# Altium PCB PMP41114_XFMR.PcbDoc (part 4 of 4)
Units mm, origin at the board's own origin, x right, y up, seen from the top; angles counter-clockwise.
Board outline 70 x 173.04 mm, 10 copper layers (Top Layer, Layer 2, Layer 3, Layer 4, Layer 5, Layer 6, Layer 7, Layer 8, Layer 9, Bottom Layer 1), stack 2.98 mm thick; 144 components, 147 nets, 541 pads, 962 vias.
Unrouted connection lines stored in the file: 2.

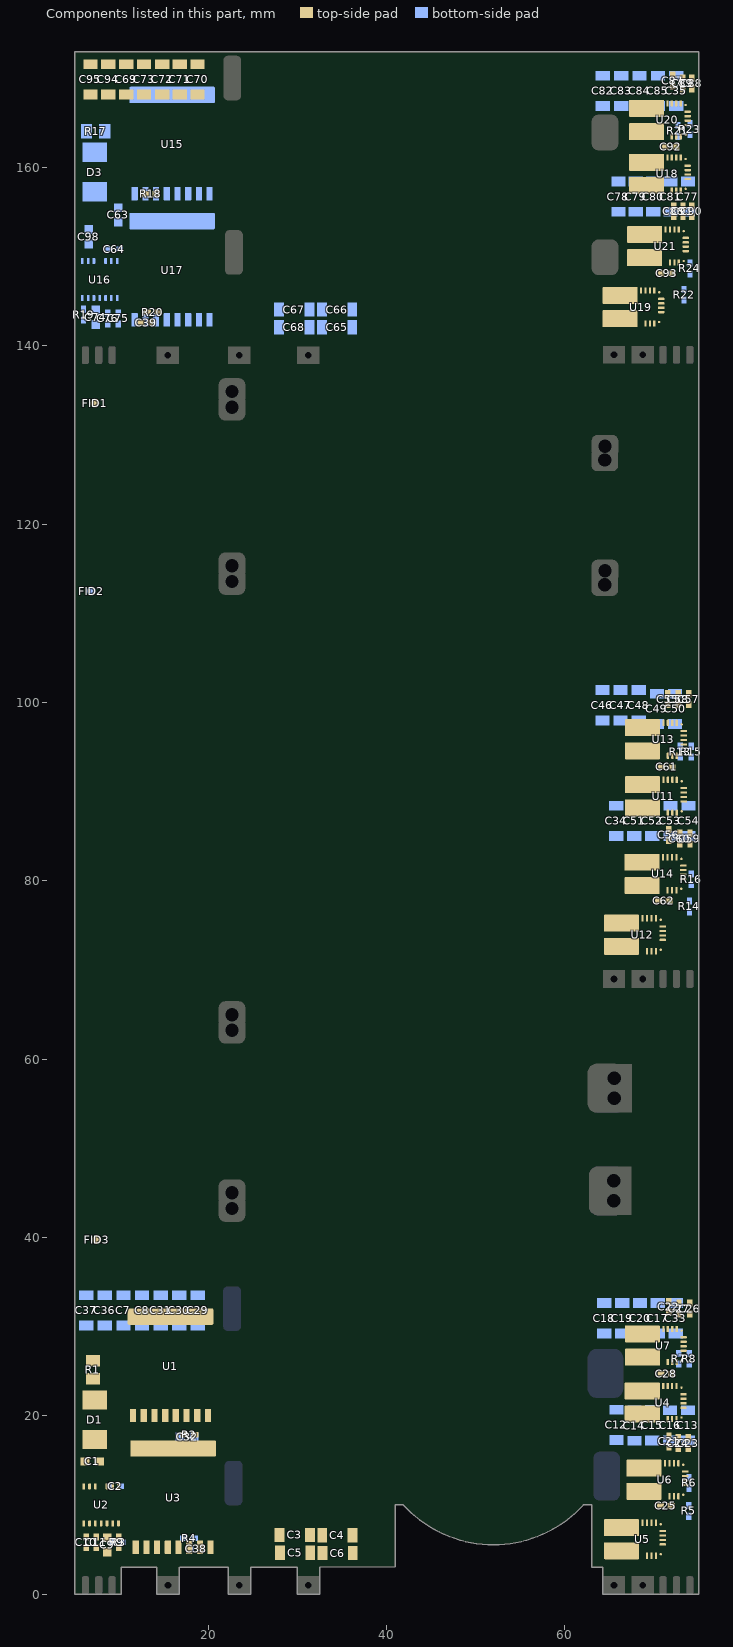
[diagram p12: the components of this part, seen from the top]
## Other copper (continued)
Layer 5:
  rectangle net B+_2: 5.479,29.71 21.197,31.729
  rectangle net Pri-SW_2: 21.821,29.443 24.74,34.307
  rectangle net Pri-Mid1_2: 35.515,3.537 37.264,7.513
  pour cut-out: 41.094,115.914 42.614,115.914 43.122,115.406 43.122,113.701 42.645,113.223 41.094,113.223
  pour cut-out: 10.564,154.799 11.055,155.291 20.429,155.291 20.914,154.805 20.914,153.478 20.404,152.967 11.056,152.967 10.564,153.46
  pour cut-out: 22.994,147.936 22.75,148.437 22.75,152.749 22.943,152.942 23.927,152.942 24.172,152.697 24.172,148.437 23.927,147.936
  pour cut-out: 15.119,157.57 cw(c15.119,158.29) 14.399,158.29 cw(c15.119,158.29) 15.119,159.01 cw(c15.119,158.29) 15.839,158.29 cw(c15.119,158.29)
  pour cut-out: 12.923,157.302 cw(c12.923,158.022) 12.203,158.022 cw(c12.923,158.022) 12.923,158.742 cw(c12.923,158.022) 13.643,158.022 cw(c12.923,158.022)
  pour cut-out: 11.02,156.256 cw(c11.02,156.976) 10.3,156.976 cw(c11.02,156.976) 11.02,157.696 cw(c11.02,156.976) 11.74,156.976 cw(c11.02,156.976)
  pour cut-out: 5.627,164.03 cw(c5.627,164.75) 4.907,164.75 cw(c5.627,164.75) 5.627,165.47 cw(c5.627,164.75) 6.347,164.75 cw(c5.627,164.75)
  pour cut-out: 5.768,153.639 cw(c5.768,154.359) 5.048,154.359 cw(c5.768,154.359) 5.768,155.079 cw(c5.768,154.359) 6.488,154.359 cw(c5.768,154.359)
  pour cut-out: 6.589,152.318 cw(c6.589,153.038) 5.869,153.038 cw(c6.589,153.038) 6.589,153.758 cw(c6.589,153.038) 7.309,153.038 cw(c6.589,153.038)
  pour cut-out: 6.589,150.718 cw(c6.589,151.438) 5.869,151.438 cw(c6.589,151.438) 6.589,152.158 cw(c6.589,151.438) 7.309,151.438 cw(c6.589,151.438)
  pour cut-out: 6.31,149.551 cw(c6.31,150.271) 5.59,150.271 cw(c6.31,150.271) 6.31,150.991 cw(c6.31,150.271) 7.03,150.271 cw(c6.31,150.271)
  pour cut-out: 52.038,79.072 cw(c52.038,87.072) 44.038,87.072 cw(c52.038,87.072) 52.038,95.072 cw(c52.038,87.072) 60.038,87.072 cw(c52.038,87.072)
  pour cut-out: 6.25,24.875 cw(c6.25,25.595) 5.53,25.595 cw(c6.25,25.595) 6.25,26.315 cw(c6.25,25.595) 6.97,25.595 cw(c6.25,25.595)
  pour cut-out: 63,130.25 63,126.056 63.785,125.271 64.5,125.271 64.5,130.25
  pour cut-out: 62.986,111.714 62.986,115.908 63.772,116.693 64.486,116.693 64.486,111.713
  pour cut-out: 10.559,164.447 11.021,164.91 20.843,164.91 21.243,164.509 21.243,158.706 20.857,158.319 10.903,158.319 10.559,158.663
  pour cut-out: 24.945,160.25 26.83,160.25 27.338,159.742 27.338,158.037 26.86,157.56 24.954,157.56 24.495,158.019 24.495,159.799
  pour cut-out: 63.251,19.14 64.592,19.14 64.753,18.979 64.753,16.437 64.501,16.185 63.275,16.185 63.04,16.419 63.04,18.929
  pour cut-out: 32.274,22.438 52.276,19.373 52.276,18.693 32.139,21.889
  text ".Layer_Name" at 15.418,-21.806 h1.52
Layer 6:
  rectangle net B+_2: 5.479,29.71 21.197,31.729
  rectangle net Pri-SW_5: 22.075,168.063 24.567,172.449
  rectangle net Pri-SW_2: 11.005,21.919 20.37,27.371
  rectangle net Pri-SW_2: 22.851,29.934 23.588,34.329
  rectangle net Pri-Mid1_2: 35.515,3.537 37.264,7.513
  rectangle net Pri-Mid1_2: 27.275,3.61 29.023,7.586
  pour cut-out: 52.038,79.072 cw(c52.038,87.072) 44.038,87.072 cw(c52.038,87.072) 52.038,95.072 cw(c52.038,87.072) 60.038,87.072 cw(c52.038,87.072)
  pour cut-out: 63,130.25 63,126.056 63.785,125.271 64.5,125.271 64.5,130.25
  pour cut-out: 62.986,111.714 62.986,115.908 63.772,116.693 64.486,116.693 64.486,111.713
  pour cut-out: 37.75,54 38.011,53.739 40.486,53.739 41,54.253 41,55.46 40.43,56.03 38.169,56.03 37.75,55.612
  pour cut-out: 63.23,157.156 64.571,157.156 64.732,156.995 64.732,154.453 64.48,154.201 63.254,154.201 63.019,154.436 63.019,156.946
  pour cut-out: 21.125,167.563 21.125,141.449 21.491,141.449 21.491,167.614
  pour cut-out: 42.449,121.29 42.449,123.151 42.753,123.455 45.474,123.455 45.636,123.293 45.636,121.286 45.355,121.006 42.733,121.006
  pour cut-out: 32.274,22.438 52.276,19.373 52.276,18.693 32.139,21.889
  pour cut-out: 63.23,19.156 64.571,19.156 64.732,18.995 64.732,16.453 64.48,16.201 63.254,16.201 63.019,16.436 63.019,18.946
  text ".Layer_Name" at 16.489,-21.556 h1.52
Layer 7:
  rectangle net Pri-SW_5: 22.854,168.114 25.048,172.5
  rectangle net Pri-Mid1_2: 35.515,3.537 37.264,7.513
  rectangle net Pri-Mid1_2: 27.275,3.61 29.023,7.586
  rectangle net Pri-SW_2: 11.005,21.919 20.37,27.371
  pour cut-out: 37.639,114.437 38.775,114.437 41,112.212 41,111.936 37.672,111.936 37.639,111.969
  pour cut-out: 23.491,8.148 22.8,8.169 22.43,8.453 22.43,14.592 22.622,14.784 23.607,14.784 23.851,14.54 23.851,8.428
  pour cut-out: 17.865,18.271 cw(c17.865,18.991) 17.145,18.991 cw(c17.865,18.991) 17.865,19.711 cw(c17.865,18.991) 18.585,18.991 cw(c17.865,18.991)
  pour cut-out: 18.654,17.982 cw(c18.654,18.702) 17.934,18.702 cw(c18.654,18.702) 18.654,19.422 cw(c18.654,18.702) 19.374,18.702 cw(c18.654,18.702)
  pour cut-out: 19.486,17.926 cw(c19.486,18.646) 18.766,18.646 cw(c19.486,18.646) 19.486,19.366 cw(c19.486,18.646) 20.206,18.646 cw(c19.486,18.646)
  pour cut-out: 5.627,164.03 cw(c5.627,164.75) 4.907,164.75 cw(c5.627,164.75) 5.627,165.47 cw(c5.627,164.75) 6.347,164.75 cw(c5.627,164.75)
  pour cut-out: 52.038,79.072 cw(c52.038,87.072) 44.038,87.072 cw(c52.038,87.072) 52.038,95.072 cw(c52.038,87.072) 60.038,87.072 cw(c52.038,87.072)
  pour cut-out: 6.25,24.875 cw(c6.25,25.595) 5.53,25.595 cw(c6.25,25.595) 6.25,26.315 cw(c6.25,25.595) 6.97,25.595 cw(c6.25,25.595)
  pour cut-out: 63,130.25 63,126.056 63.785,125.271 64.5,125.271 64.5,130.25
  pour cut-out: 62.986,111.714 62.986,115.908 63.772,116.693 64.486,116.693 64.486,111.713
  pour cut-out: 36.508,51.807 36.508,53.148 36.757,53.397 38.88,53.397 39.275,53.002 39.275,51.904 38.898,51.526 36.789,51.526
  pour cut-out: 63.203,157.25 64.518,157.25 64.794,156.973 64.794,154.223 64.5,153.929 63.21,153.929 62.864,154.275 62.864,156.911
  pour cut-out: 24.534,161.537 25.088,162.09 26.904,162.09 27.42,161.574 27.42,160.456 27.043,160.078 24.977,160.078 24.534,160.521
  pour cut-out: 10.372,27.538 10.834,28 20.656,28 21.057,27.599 21.057,21.796 20.67,21.409 10.716,21.409 10.372,21.754
  pour cut-out: 32.274,22.438 52.276,19.373 52.276,18.693 32.139,21.889
  pour cut-out: 63.298,19.187 64.544,19.187 64.753,18.979 64.753,16.437 64.41,16.094 63.366,16.094 63.04,16.419 63.04,18.929
  text ".Layer_Name" at 17.518,-21.806 h1.52
Layer 8:
  rectangle net Pri-SW_2: 11.005,21.919 20.37,27.371
  rectangle net Pri-SW_5: 24.88,160.462 26.992,161.755
  rectangle net Pri-SW_5: 22.854,168.114 25.347,172.5
  rectangle net Pri-Mid1_2: 35.515,3.537 37.264,7.513
  pour cut-out: 37.639,114.437 38.775,114.437 41,112.212 41,111.936 37.672,111.936 37.639,111.969
  pour cut-out: 22.487,34.513 23.908,34.469 23.908,29.862 23.716,29.669 22.731,29.669 22.487,29.914
  pour cut-out: 28.524,22.623 28.524,24.815 25.326,24.815 24.804,24.294 24.804,23.109 25.29,22.623
  pour cut-out: 6.701,12.261 cw(c6.701,12.981) 5.981,12.981 cw(c6.701,12.981) 6.701,13.701 cw(c6.701,12.981) 7.421,12.981 cw(c6.701,12.981)
  pour cut-out: 5.808,12.572 cw(c5.808,13.292) 5.088,13.292 cw(c5.808,13.292) 5.808,14.012 cw(c5.808,13.292) 6.528,13.292 cw(c5.808,13.292)
  pour cut-out: 6.678,13.09 cw(c6.678,13.81) 5.958,13.81 cw(c6.678,13.81) 6.678,14.53 cw(c6.678,13.81) 7.398,13.81 cw(c6.678,13.81)
  pour cut-out: 6.25,24.875 cw(c6.25,25.595) 5.53,25.595 cw(c6.25,25.595) 6.25,26.315 cw(c6.25,25.595) 6.97,25.595 cw(c6.25,25.595)
  pour cut-out: 10.372,27.538 10.834,28 20.656,28 21.057,27.599 21.057,21.796 20.67,21.409 10.716,21.409 10.372,21.754
  pour cut-out: 18.654,17.982 cw(c18.654,18.702) 17.934,18.702 cw(c18.654,18.702) 18.654,19.422 cw(c18.654,18.702) 19.374,18.702 cw(c18.654,18.702)
  pour cut-out: 17.865,18.271 cw(c17.865,18.991) 17.145,18.991 cw(c17.865,18.991) 17.865,19.711 cw(c17.865,18.991) 18.585,18.991 cw(c17.865,18.991)
  pour cut-out: 19.486,17.926 cw(c19.486,18.646) 18.766,18.646 cw(c19.486,18.646) 19.486,19.366 cw(c19.486,18.646) 20.206,18.646 cw(c19.486,18.646)
  pour cut-out: 23.491,8.148 22.8,8.169 22.43,8.453 22.43,14.592 22.622,14.784 23.607,14.784 23.851,14.54 23.851,8.428
  pour cut-out: 10.564,154.799 11.055,155.291 20.429,155.291 20.914,154.805 20.914,153.478 20.404,152.967 11.056,152.967 10.564,153.46
  pour cut-out: 22.994,147.936 22.75,148.437 22.75,152.749 22.943,152.942 23.927,152.942 24.172,152.697 24.172,148.437 23.927,147.936
  pour cut-out: 23.238,167.686 cw(c23.238,168.406) 22.518,168.406 cw(c23.238,168.406) 23.238,169.126 cw(c23.238,168.406) 23.958,168.406 cw(c23.238,168.406)
  pour cut-out: 23.235,169.117 cw(c23.235,169.837) 22.515,169.837 cw(c23.235,169.837) 23.235,170.557 cw(c23.235,169.837) 23.955,169.837 cw(c23.235,169.837)
  pour cut-out: 23.238,168.406 cw(c23.238,169.126) 22.518,169.126 cw(c23.238,169.126) 23.238,169.846 cw(c23.238,169.126) 23.958,169.126 cw(c23.238,169.126)
  pour cut-out: 6.31,149.551 cw(c6.31,150.271) 5.59,150.271 cw(c6.31,150.271) 6.31,150.991 cw(c6.31,150.271) 7.03,150.271 cw(c6.31,150.271)
  pour cut-out: 6.589,150.718 cw(c6.589,151.438) 5.869,151.438 cw(c6.589,151.438) 6.589,152.158 cw(c6.589,151.438) 7.309,151.438 cw(c6.589,151.438)
  pour cut-out: 6.589,152.318 cw(c6.589,153.038) 5.869,153.038 cw(c6.589,153.038) 6.589,153.758 cw(c6.589,153.038) 7.309,153.038 cw(c6.589,153.038)
  pour cut-out: 5.768,153.639 cw(c5.768,154.359) 5.048,154.359 cw(c5.768,154.359) 5.768,155.079 cw(c5.768,154.359) 6.488,154.359 cw(c5.768,154.359)
  pour cut-out: 5.627,164.03 cw(c5.627,164.75) 4.907,164.75 cw(c5.627,164.75) 5.627,165.47 cw(c5.627,164.75) 6.347,164.75 cw(c5.627,164.75)
  pour cut-out: 11.02,156.256 cw(c11.02,156.976) 10.3,156.976 cw(c11.02,156.976) 11.02,157.696 cw(c11.02,156.976) 11.74,156.976 cw(c11.02,156.976)
  pour cut-out: 12.923,157.302 cw(c12.923,158.022) 12.203,158.022 cw(c12.923,158.022) 12.923,158.742 cw(c12.923,158.022) 13.643,158.022 cw(c12.923,158.022)
  pour cut-out: 15.119,157.57 cw(c15.119,158.29) 14.399,158.29 cw(c15.119,158.29) 15.119,159.01 cw(c15.119,158.29) 15.839,158.29 cw(c15.119,158.29)
  pour cut-out: 52.038,79.072 cw(c52.038,87.072) 44.038,87.072 cw(c52.038,87.072) 52.038,95.072 cw(c52.038,87.072) 60.038,87.072 cw(c52.038,87.072)
  pour cut-out: 6.25,24.875 cw(c6.25,25.595) 5.53,25.595 cw(c6.25,25.595) 6.25,26.315 cw(c6.25,25.595) 6.97,25.595 cw(c6.25,25.595)
  pour cut-out: 63,130.25 63,126.056 63.785,125.271 64.5,125.271 64.5,130.25
  pour cut-out: 62.986,111.714 62.986,115.908 63.772,116.693 64.486,116.693 64.486,111.713
  pour cut-out: 10.559,164.447 11.021,164.91 20.843,164.91 21.243,164.509 21.243,158.706 20.857,158.319 10.903,158.319 10.559,158.663
  pour cut-out: 63.298,87.187 64.544,87.187 64.753,86.979 64.753,84.437 64.41,84.094 63.366,84.094 63.04,84.419 63.04,86.929
  pour cut-out: 63.298,19.187 64.544,19.187 64.753,18.979 64.753,16.437 64.41,16.094 63.366,16.094 63.04,16.419 63.04,18.929
  pour cut-out: 36.527,52.047 36.527,52.953 37.042,53.469 38.982,53.469 39.276,53.175 39.276,51.519 37.055,51.519
  text ".Layer_Name" at 18.685,-21.556 h1.52
Layer 2:
  rectangle net 54Vout_5: 64.25,138.321 66.756,140.899
  rectangle net 54Vout_4: 64.25,68.321 66.756,70.899
  rectangle net 54Vout_2: 64.25,0.321 66.756,2.899
  rectangle net Pri-SW_2: 22.851,29.523 26.129,34.409
  rectangle net Pri-SW_2: 22.851,29.545 23.588,34.409
  rectangle net Pri-Mid1_2: 27.053,3.657 28.725,7.513
  rectangle net Pri-Mid1_2: 35.515,3.537 37.264,7.513
  rectangle net Pri-SW_2: 11.231,21.858 20.482,27.384
  pour cut-out: 24.692,161.794 24.989,162.09 27.324,162.09 27.42,161.994 27.42,160.456 27.043,160.078 24.977,160.078 24.692,160.363
  pour cut-out: 41.043,115.853 42.594,115.853 43.038,115.408 43.038,113.351 41.076,113.351 41.043,113.384
  pour cut-out: 37.639,114.437 38.775,114.437 41,112.212 41,111.936 37.672,111.936 37.639,111.969
  pour cut-out: 31.957,117.944 cw(c31.957,124.462) 25.439,124.462 cw(c31.957,124.462) 31.957,130.979 cw(c31.957,124.462) 38.474,124.462 cw(c31.957,124.462)
  pour cut-out: 52.038,79.072 cw(c52.038,87.072) 44.038,87.072 cw(c52.038,87.072) 52.038,95.072 cw(c52.038,87.072) 60.038,87.072 cw(c52.038,87.072)
  pour cut-out: 19.264,30.282 cw(c19.264,31.002) 18.544,31.002 cw(c19.264,31.002) 19.264,31.722 cw(c19.264,31.002) 19.984,31.002 cw(c19.264,31.002)
  pour cut-out: 19.264,29.562 cw(c19.264,30.282) 18.544,30.282 cw(c19.264,30.282) 19.264,31.002 cw(c19.264,30.282) 19.984,30.282 cw(c19.264,30.282)
  pour cut-out: 16.858,30.275 cw(c16.858,30.995) 16.138,30.995 cw(c16.858,30.995) 16.858,31.715 cw(c16.858,30.995) 17.578,30.995 cw(c16.858,30.995)
  pour cut-out: 16.858,29.555 cw(c16.858,30.275) 16.138,30.275 cw(c16.858,30.275) 16.858,30.995 cw(c16.858,30.275) 17.578,30.275 cw(c16.858,30.275)
  pour cut-out: 14.453,30.269 cw(c14.453,30.989) 13.733,30.989 cw(c14.453,30.989) 14.453,31.709 cw(c14.453,30.989) 15.173,30.989 cw(c14.453,30.989)
  pour cut-out: 14.453,29.549 cw(c14.453,30.269) 13.733,30.269 cw(c14.453,30.269) 14.453,30.989 cw(c14.453,30.269) 15.173,30.269 cw(c14.453,30.269)
  pour cut-out: 12.048,29.542 cw(c12.048,30.262) 11.328,30.262 cw(c12.048,30.262) 12.048,30.982 cw(c12.048,30.262) 12.767,30.262 cw(c12.048,30.262)
  pour cut-out: 12.048,30.262 cw(c12.048,30.982) 11.328,30.982 cw(c12.048,30.982) 12.048,31.702 cw(c12.048,30.982) 12.767,30.982 cw(c12.048,30.982)
  pour cut-out: 9.642,29.536 cw(c9.642,30.256) 8.922,30.256 cw(c9.642,30.256) 9.642,30.976 cw(c9.642,30.256) 10.362,30.256 cw(c9.642,30.256)
  pour cut-out: 9.642,30.256 cw(c9.642,30.976) 8.922,30.976 cw(c9.642,30.976) 9.642,31.696 cw(c9.642,30.976) 10.362,30.976 cw(c9.642,30.976)
  pour cut-out: 7.237,29.526 cw(c7.237,30.246) 6.517,30.246 cw(c7.237,30.246) 7.237,30.966 cw(c7.237,30.246) 7.957,30.246 cw(c7.237,30.246)
  pour cut-out: 7.237,30.249 cw(c7.237,30.969) 6.517,30.969 cw(c7.237,30.969) 7.237,31.689 cw(c7.237,30.969) 7.957,30.969 cw(c7.237,30.969)
  pour cut-out: 63,130.25 63,126.056 63.785,125.271 64.5,125.271 64.5,130.25
  pour cut-out: 62.986,111.714 62.986,115.908 63.772,116.693 64.486,116.693 64.486,111.713
  pour cut-out: 32.311,55.872 52.003,52.856 51.561,49.158 31.442,52.331
  pour cut-out: 10.588,27.528 10.931,27.871 20.584,27.871 20.938,27.517 20.938,21.791 20.441,21.294 10.95,21.294 10.588,21.655
  pour cut-out: 32.038,124.719 51.867,121.681 51.691,120.205 31.703,123.358
  text ".Layer_Name" at 15.454,-21.556 h1.52
Layer 9:
  rectangle net Pri-SW_5: 24.88,160.462 26.992,161.755
  rectangle net Pri-SW_5: 22.776,167.712 24.809,172.5
  rectangle net Pri-SW_2: 22.243,29.581 24.172,34.409
  rectangle net Pri-Mid1_2: 35.515,3.537 37.264,7.513
  pour cut-out: 37.857,54.232 37.857,55.573 38.106,55.822 40.229,55.822 40.624,55.427 40.624,54.329 40.247,53.951 38.138,53.951
  pour cut-out: 10.564,154.799 11.055,155.291 20.429,155.291 20.914,154.805 20.914,153.478 20.404,152.967 11.056,152.967 10.564,153.46
  pour cut-out: 11.02,156.256 cw(c11.02,156.976) 10.3,156.976 cw(c11.02,156.976) 11.02,157.696 cw(c11.02,156.976) 11.74,156.976 cw(c11.02,156.976)
  pour cut-out: 12.923,157.302 cw(c12.923,158.022) 12.203,158.022 cw(c12.923,158.022) 12.923,158.742 cw(c12.923,158.022) 13.643,158.022 cw(c12.923,158.022)
  pour cut-out: 15.119,157.57 cw(c15.119,158.29) 14.399,158.29 cw(c15.119,158.29) 15.119,159.01 cw(c15.119,158.29) 15.839,158.29 cw(c15.119,158.29)
  pour cut-out: 18.943,168.023 cw(c18.943,168.743) 18.223,168.743 cw(c18.943,168.743) 18.943,169.463 cw(c18.943,168.743) 19.663,168.743 cw(c18.943,168.743)
  pour cut-out: 18.943,167.303 cw(c18.943,168.023) 18.223,168.023 cw(c18.943,168.023) 18.943,168.743 cw(c18.943,168.023) 19.663,168.023 cw(c18.943,168.023)
  pour cut-out: 16.537,168.017 cw(c16.537,168.737) 15.817,168.737 cw(c16.537,168.737) 16.537,169.457 cw(c16.537,168.737) 17.257,168.737 cw(c16.537,168.737)
  pour cut-out: 16.537,167.297 cw(c16.537,168.017) 15.817,168.017 cw(c16.537,168.017) 16.537,168.737 cw(c16.537,168.017) 17.257,168.017 cw(c16.537,168.017)
  pour cut-out: 14.132,168.01 cw(c14.132,168.73) 13.412,168.73 cw(c14.132,168.73) 14.132,169.45 cw(c14.132,168.73) 14.852,168.73 cw(c14.132,168.73)
  pour cut-out: 14.132,167.29 cw(c14.132,168.01) 13.412,168.01 cw(c14.132,168.01) 14.132,168.73 cw(c14.132,168.01) 14.852,168.01 cw(c14.132,168.01)
  pour cut-out: 11.726,167.284 cw(c11.726,168.004) 11.006,168.004 cw(c11.726,168.004) 11.726,168.724 cw(c11.726,168.004) 12.446,168.004 cw(c11.726,168.004)
  pour cut-out: 11.726,168.004 cw(c11.726,168.724) 11.006,168.724 cw(c11.726,168.724) 11.726,169.444 cw(c11.726,168.724) 12.446,168.724 cw(c11.726,168.724)
  pour cut-out: 9.321,167.277 cw(c9.321,167.997) 8.601,167.997 cw(c9.321,167.997) 9.321,168.717 cw(c9.321,167.997) 10.041,167.997 cw(c9.321,167.997)
  pour cut-out: 9.321,167.997 cw(c9.321,168.717) 8.601,168.717 cw(c9.321,168.717) 9.321,169.437 cw(c9.321,168.717) 10.041,168.717 cw(c9.321,168.717)
  pour cut-out: 6.915,167.268 cw(c6.915,167.987) 6.196,167.987 cw(c6.915,167.987) 6.915,168.707 cw(c6.915,167.987) 7.635,167.987 cw(c6.915,167.987)
  pour cut-out: 6.915,167.991 cw(c6.915,168.711) 6.196,168.711 cw(c6.915,168.711) 6.915,169.431 cw(c6.915,168.711) 7.635,168.711 cw(c6.915,168.711)
  pour cut-out: 52.038,79.072 cw(c52.038,87.072) 44.038,87.072 cw(c52.038,87.072) 52.038,95.072 cw(c52.038,87.072) 60.038,87.072 cw(c52.038,87.072)
  pour cut-out: 6.25,24.875 cw(c6.25,25.595) 5.53,25.595 cw(c6.25,25.595) 6.25,26.315 cw(c6.25,25.595) 6.97,25.595 cw(c6.25,25.595)
  pour cut-out: 62.986,111.714 62.986,115.908 63.772,116.693 64.486,116.693 64.486,111.713
  pour cut-out: 63,130.25 63,126.056 63.785,125.271 64.5,125.271 64.5,130.25
  pour cut-out: 10.559,164.447 11.021,164.91 20.843,164.91 21.243,164.509 21.243,158.706 20.857,158.319 10.903,158.319 10.559,158.663
  pour cut-out: 42.449,121.29 42.449,123.151 42.753,123.455 44.9,123.455 45.216,123.14 45.216,121.299 44.923,121.006 42.733,121.006
  pour cut-out: 36.508,51.807 36.508,53.148 36.757,53.397 38.88,53.397 39.275,53.002 39.275,51.904 38.898,51.526 36.789,51.526
  text ".Layer_Name" at 17.518,-21.556 h1.52
Bottom Layer 1:
  rectangle net Pri-Mid1_5: 22.802,148.1 23.993,152.348
  rectangle net Pri-Mid1_5: 35.367,141.21 37.473,145.589
  rectangle net Pri-Mid1_5: 26.868,141.194 28.534,145.382
  rectangle net Pri-SW_5: 22.559,167.211 23.749,172.5
  rectangle net Pri-Mid1_2: 27.053,3.657 28.725,7.513
  rectangle net Pri-Mid1_2: 35.515,3.537 37.264,7.513
  pour cut-out: 6.25,24.677 cw(c6.25,25.664) 5.263,25.664 cw(c6.217,25.631) 6.25,26.584 cw(c6.25,25.595) 7.239,25.595 cw(c6.286,25.631)
  text ".Layer_Name" at 14.656,-21.806 h1.52
Multi-Layer:
  rectangle net 54Vout_5: 64.25,138.321 66.756,140.899
  rectangle net 54Vout_4: 64.25,68.321 66.756,70.899
  rectangle net 54Vout_2: 64.25,0.321 66.756,2.899
  rectangle net B-_5: 11.192,144.862 20.557,150.254
  rectangle net Pri-SW_5: 11.192,159.01 20.557,164.403

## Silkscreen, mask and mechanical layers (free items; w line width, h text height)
Top Overlay:
  lines w0.254: 41,27.919 45.469,20.555 ; 41.096,9.603 45.565,16.967 ; 58.435,16.967 62.904,9.603 ; 58.531,20.555 63,27.919
  text "'.PRJ_Number'" at 44.528,9.333 h2
  text "H" at 5.958,2.966 h0.5
  text "G" at 7.578,2.966 h0.5
  text "L" at 9.127,2.966 h0.5
  text ".Layer_Name" at 14.656,-21.806 h1.52
Bottom Overlay:
  text "Z" at 9.407,3.226 h0.5
  text "V" at 6.461,3.207 h0.5
  text "G" at 7.81,3.207 h0.5
  text "54V" at 66.286,3.117 h0.5
  text "0V" at 69.044,3.117 h0.5
  text "PGND" at 16.52,3.039 h0.5
  text "HV" at 23.802,3.039 h0.5
  text "Mid" at 31.988,3.051 h0.5
  text "BH" at 72.739,2.557 h0.5
  text "AH" at 74.335,2.576 h0.5
  text "G" at 71.069,2.528 h0.5
  text ".Layer_Name" at 14.656,-21.806 h1.52
Top Paste:
  text ".Layer_Name" at 14.656,-21.806 h1.52
Bottom Paste:
  text ".Layer_Name" at 14.656,-21.806 h1.52
Top Solder:
  region: 20.63,144.688 20.63,151.273 10.95,151.273 10.95,144.688
  text ".Layer_Name" at 14.656,-21.806 h1.52
  text ".Layer_Name" at 14.656,-21.806 h1.52
Bottom Solder:
  region: 11.157,14.686 11.157,7.094 20.565,7.094 20.565,14.686
  region: 21.197,20.096 21.197,27.697 10.197,27.697 10.197,20.096
  text ".Layer_Name" at 14.656,-21.806 h1.52
Drill Guide:
  text ".Layer_Name" at 14.656,-21.806 h1.52
M1 Board Outline:
  drawing of 197 lines, arcs and shapes, not listed
  text "Bottom Layer" at 9.473,194.817 h0.76
  text "Bottom Layer" at 71.646,194.75 h0.76
  text "3+3 sec" at 59.652,192.6 h0.76
  text "3mm" at 72.055,192.6 h0.76
  text "4T pri" at 40.652,192.559 h0.76
  text "3mm" at 6.055,192.51 h0.76
  text "4T Lr" at 29.829,192.51 h0.76
  text "TopLayer" at 9.374,190.21 h0.76
  text "TopLayer" at 71.547,190.144 h0.76
  text "3mm" at 62.845,189.578 h0.76
  text "2T Lr" at 29.738,189.573 h0.76
  text "3mm" at 23.183,189.425 h0.76
  text "7T pri" at 40.652,189.425 h0.76
  text "3mm" at 71.902,186.614 h0.76
  text "0T pri" at 40.652,186.582 h0.76
  text "3+3+3 sec" at 59.652,186.461 h0.76
  text "7T pri" at 40.652,183.656 h0.76
  text "3mm" at 23.238,183.402 h0.76
  text "2T Lr" at 29.646,183.402 h0.76
  text "3mm" at 62.865,183.402 h0.76
  text "Bottom Layer" at 71.727,183.156 h0.76
  text "Bottom Layer" at 9.671,182.86 h0.76
  text "3+3 sec" at 59.902,180.705 h0.76
  text "3mm" at 5.903,180.659 h0.76
  text "4T pri" at 40.652,180.478 h0.76
  text "3mm" at 72.055,180.402 h0.76
  text "4T Lr" at 29.562,180.37 h0.76
  text "TopLayer" at 9.572,178.254 h0.76
  text "TopLayer" at 71.745,178.187 h0.76
  text ".Layer_Name" at 14.656,-21.806 h1.52
M2 Board Dimensions:
  rectangle: 0,-6.985 3.175,-3.81
  rectangle: 3.175,-10.16 12.7,-6.985
  lines w0.178: 0,-6.985 25.4,-6.985 ; 3.175,-10.16 3.175,-3.81 ; 6.35,-10.16 6.35,-3.81 ; 12.7,-10.16 12.7,-3.81 ; 19.05,-10.16 19.05,-3.81 ; 0,-10.16 25.4,-10.16 25.4,-3.81 0,-3.81 0,-10.16
  text ".Layer_Name" at 14.656,-21.806 h1.52
M3 3D STEP Top:
  text ".Layer_Name" at 14.656,-21.806 h1.52
M4 3D STEP Bottom:
  text ".Layer_Name" at 14.656,-21.806 h1.52
M5 Assembly Top:
  lines w0.254: -7.417,-23.626 160.223,-23.626 ; -7.417,-18.462 160.274,-18.462 ; -7.417,-13.297 -7.417,-28.791 94.31,-28.791 160.274,-28.791 160.274,-13.297 -7.404,-13.297 -7.404,-28.791 32.614,-28.791 ; 55.194,-28.791 55.194,-13.297 ; 87.376,-18.462 87.376,-13.297 ; 108.712,-18.462 108.712,-13.297 ; 124.511,-28.956 124.511,-23.804
  text "COMPONENTS MARKED 'DNP' SHOULD NOT BE POPULATED." at 29.299,-8.09 h1.52
  text "ASSEMBLY VARIANT:" at 29.286,-11.024 h1.52
  text ".VariantName" at 55.601,-11.024 h1.52
  text "PCB VIEWED FROM TOP SIDE" at -5.804,-16.654 h1.52
  text "BOARD #:" at 57.099,-16.654 h1.52
  text ".PRJ_Number" at 70.955,-16.654 h1.52
  text "REV:" at 92.405,-16.654 h1.52
  text ".PCB_Rev" at 99.809,-16.654 h1.52
  text "SVN REV:" at 113.69,-16.654 h1.52
  text ".VersionControl_RevNumber" at 126.543,-16.654 h1.52
  text "TID #:" at 57.099,-21.819 h1.52
  text ".TID" at 70.955,-21.819 h1.52
  text "PLOT NAME =" at -5.804,-27.034 h1.52
  text ".plot_File_Name" at 14.656,-27.034 h1.52
  text "GENERATED    :" at 57.15,-27.034 h1.52
  text ".Print_Date" at 79.235,-27.034 h1.52
  text ".Print_Time" at 97.752,-27.034 h1.52
  text "TEXAS INSTRUMENTS" at 129.87,-27.034 h1.52
M6 Assembly Bottom:
  lines w0.254: -7.429,-18.474 160.261,-18.474 ; -7.379,-23.639 160.261,-23.639 ; 28.334,-28.969 28.334,-23.817 ; 44.133,-18.474 44.133,-13.31 ; 65.468,-18.474 65.468,-13.31 ; 97.65,-28.804 97.65,-13.31 ; 120.231,-28.804 160.249,-28.804 160.249,-13.31 -7.429,-13.31 -7.429,-28.804 58.534,-28.804 160.261,-28.804 160.261,-13.31
  text "COMPONENTS MARKED 'DNP' SHOULD NOT BE POPULATED." at 154.991,-8.077 h1.52
  text ".VariantName" at 128.473,-11.024 h1.52
  text "ASSEMBLY VARIANT:" at 154.864,-11.024 h1.52
  text ".VersionControl_RevNumber" at 26.302,-16.667 h1.52
  text "SVN REV:" at 39.154,-16.667 h1.52
  text ".PCB_Rev" at 53.035,-16.667 h1.52
  text "REV:" at 60.439,-16.667 h1.52
  text ".PRJ_Number" at 81.89,-16.667 h1.52
  text "BOARD #:" at 95.745,-16.667 h1.52
  text "PCB VIEWED FROM BOTTOM SIDE" at 158.648,-16.667 h1.52
  text ".TID" at 81.89,-21.831 h1.52
  text "TID #:" at 95.745,-21.831 h1.52
  text "TEXAS INSTRUMENTS" at 22.974,-27.047 h1.52
  text ".Print_Time" at 55.093,-27.047 h1.52
  text ".Print_Date" at 73.609,-27.047 h1.52
  text "GENERATED    :" at 95.694,-27.047 h1.52
  text ".plot_File_Name" at 138.189,-27.047 h1.52
  text "PLOT NAME =" at 158.648,-27.047 h1.52
M9 Title Sheet:
  drawing of 57 lines, arcs and shapes, not listed
  text "1" at 18.792,204.127 h1.78
  text "2" at 82.182,204.127 h1.78
  text "3" at 145.411,204.127 h1.78
  text "4" at 209.08,204.127 h1.78
  text "5" at 272.555,204.127 h1.78
  text "6" at 336.182,204.127 h1.78
  text "A" at -10.579,175.095 h1.78
  text "A" at 365.341,175.095 h1.78
  text "B" at -10.579,114.643 h1.78
  text "B" at 365.341,114.643 h1.78
  text "C" at -10.579,54.318 h1.78
  text "C" at 365.341,54.318 h1.78
  text "PROJECT TITLE:" at 288.125,7.048 h1.14
  text ".PRJ_Title" at 289.395,3.662 h1.78
  text "DESIGNED FOR:" at 288.125,-0.597 h1.14
  text ".PRJ_Customer" at 289.395,-4.153 h1.78
  text "D" at -10.579,-5.88 h1.78
  text "D" at 365.341,-5.88 h1.78
  text "FILE NAME:" at 288.125,-8.217 h1.14
  text ".PCB_File_Name_No_Path" at 289.395,-11.265 h1.78
  text "Texas Instruments (TI) and/or its licensors do not warrant the accuracy or completeness of this specification" at 161.9,-15.376 h1.14
  text "ENGINEER:" at 288.125,-15.583 h1.14
  text "LAYOUT BY:" at 326.352,-15.583 h1.14
  text "or any information contained therein. TI and/or its licensors do not warrant that this design will meet" at 160.757,-18.237 h1.14
  text ".PRJ_Engineer" at 289.395,-19.52 h1.78
  text ".PCB_Layout" at 327.635,-19.52 h1.78
  text "the specifications, will be suitable for your application or fit for any particular purpose, or will operate in" at 160.757,-21.099 h1.14
  text ".Layer_Name" at 14.656,-21.806 h1.52
  text "ALTIUM DESIGNER VERSION:" at 326.352,-23.457 h1.14
  text "an implementation. TI and/or its licensors do not warrant that the design is production worthy. You should" at 160.757,-23.961 h1.14
  text "completely validate and test your design implementation to confirm the system functionality for your application." at 161.9,-26.822 h1.14
  text ".print_Scale" at 289.395,-26.843 h1.78
  text ".Application_BuildNumber" at 327.635,-26.843 h1.78
  text "1" at 18.792,-32.093 h1.78
  text "2" at 82.182,-32.093 h1.78
  text "3" at 145.411,-32.093 h1.78
  text "4" at 209.08,-32.093 h1.78
  text "5" at 272.555,-32.093 h1.78
  text "6" at 336.182,-32.093 h1.78
M10 Fab Notes:
  drawing of 189 lines, arcs and shapes, not listed
  text "DESIGN INFORMATION" at 314.503,161.447 h1.52
  text "MIN. TRACK WIDTH:" at 298.131,158.091 h1.52
  text "8" at 325.976,158.091 h1.52
  text "MIL" at 329.907,158.091 h1.52
  text "7.874" at 321.75,155 h1.52
  text "MIN. CLEARANCE:" at 298.131,154.938 h1.52
  text "MIL" at 329.907,154.938 h1.52
  text "MIN. VIA PAD SIZE:" at 298.131,151.785 h1.52
  text "24" at 325.214,151.785 h1.52
  text "MIL" at 329.907,151.785 h1.52
  text "0.05mm (2MIL)" at 315.784,148.486 h1.52
  text "MINIMUM ANNULAR RING" at 289.769,148.277 h1.52
  text "EXTERNAL" at 333.768,148.277 h1.52
  text "PER" at 294.849,145.48 h1.52
  text "IPC-D-275 CLASS 2 LEVEL C" at 300.437,145.48 h1.52
  text "MIL, HOLES" at 338.238,142.928 h1.52
  text "+/-" at 328.27,142.709 h1.52
  text "+/-" at 349.961,142.709 h1.52
  text "REGISTRATION TOLERANCES:" at 289.769,142.682 h1.52
  text "METAL" at 320.243,142.682 h1.52
  text "5" at 334.879,142.683 h1.52
  text "3" at 356.037,142.683 h1.52
  text "MIL" at 358.99,142.682 h1.52
  text "HOLE SIZE TOLERANCE (UNLESS OTHERWISE SPECIFIED):" at 289.769,140.185 h1.52
  text "+/-" at 349.961,140.112 h1.52
  text "3" at 356.037,140.085 h1.52
  text "MIL" at 358.99,140.085 h1.52
  text "MATERIAL:" at 287.87,136.589 h1.52
  text "FR-4 High Tg" at 312.926,133.324 h1.52
  text "X" at 309.257,133.122 h1.52
  text "FR-4" at 298.563,133.007 h1.52
  text "OTHER" at 336.358,133.007 h1.52
  text "62 MIL (1.6mm) +/-10%" at 306.694,129.374 h1.52
  text "X" at 303.643,129.312 h1.52
  text "THICKNESS:" at 289.769,129.165 h1.52
  text "OTHER" at 339.33,129.165 h1.52
  text "TOLERANCE:" at 289.769,125.652 h1.52
  text "X" at 311.314,125.652 h1.52
  text "ANSI IPC-6012 TYPE 3 CLASS 2" at 315.836,125.652 h1.52
  text "OTHER +/-" at 315.835,121.989 h1.52
  text "BOW & TWIST:" at 289.769,118.302 h1.52
  text "X" at 311.314,118.302 h1.52
  text "ANSI IPC-6012 TYPE 3 CLASS 2" at 315.836,118.302 h1.52
  text "OTHER +/-" at 315.835,114.576 h1.52
  text "DRILLING:" at 287.87,111.258 h1.52
  text "NC_DRILL FILES" at 332.599,108.586 h1.52
  text "REFERENCE:" at 289.769,108.486 h1.52
  text "X" at 306.463,108.484 h1.52
  text "AS SHOWN" at 310.984,108.486 h1.52
  text "X" at 329.348,108.486 h1.52
  text "OTHER" at 340.168,104.873 h1.52
  text "PTH COPPER THICKNESS:" at 289.761,104.783 h1.52
  text "X" at 318.697,104.783 h1.52
  text "20-30 um" at 321.948,104.783 h1.52
  text "BOARD FINISH:" at 287.87,101.034 h1.52
  text "SILKSCREEN:" at 291.812,98.237 h1.52
  text "X" at 316.14,98.237 h1.52
  text "TOP" at 319.112,98.237 h1.52
  text "X" at 329.094,98.237 h1.52
  text "BOTTOM" at 332.091,98.237 h1.52
  text "SILKSCREEN COLOR:" at 291.812,94.295 h1.52
  text "X" at 316.115,94.295 h1.52
  text "WHITE" at 319.112,94.295 h1.52
  text "OTHER" at 332.091,94.295 h1.52
  text "X" at 319.442,90.652 h1.52
  text "GREEN" at 322.439,90.652 h1.52
  text "OTHER" at 338.136,90.652 h1.52
  text "SOLDER RESIST COLOR:" at 291.812,90.477 h1.52
  text "X" at 319.442,86.734 h1.52
  text "MATTE" at 322.439,86.734 h1.52
  text "SEMI-GLOSS" at 338.125,86.717 h1.52
  text "IMMERSION GOLD (ENIG)" at 314.819,82.345 h1.52
  text "ENEPIG" at 348.793,82.162 h1.52
  text "SURFACE FINISH:" at 287.87,82.136 h1.52
  text "X" at 310.298,82.136 h1.52
  text "IMM. TIN/SILVER OR EQUIV" at 296.24,78.649 h1.52
  text "OTHER" at 332.599,78.549 h1.52
  text "ARRAY/PANEL:" at 287.87,74.602 h1.52
  text "CUT AND TRIM PER M1 BOARD OUTLINE" at 314.819,74.393 h1.52
  text "N.C. ROUTE" at 314.819,70.94 h1.52
  text "X" at 332.295,70.94 h1.52
  text "V. SCORE" at 336.816,70.94 h1.52
  text "CERTIFICATION:" at 287.87,67.66 h1.52
  text "MATERIALS AND WORKMANSHIP FOR ALL PCBS" at 306.285,67.66 h1.52
  text "TO MEET OR EXCEED THE REQUIREMENTS OF:" at 306.285,65.271 h1.52
  text "X" at 297.078,62.003 h1.52
  text "ANSI IPC-A-600F CLASS ->" at 300.329,62.003 h1.52
  text "X" at 342.188,62.003 h1.52
  text "2" at 344.982,62.003 h1.52
  text "1" at 336.981,61.965 h1.52
  text "3" at 353.973,61.965 h1.52
  text "X" at 317.702,58.252 h1.52
  text "RoHS" at 320.953,58.252 h1.52
  text "OTHER" at 337.321,58.252 h1.52
  text "PER ORDER" at 347.407,58.252 h1.52
  text "ALL BOARDS MUST MEET OR EXCEED UL94-V0 REQUIREMENTS." at 288.569,54.345 h1.52
  text "PCB MUST BEAR THE UL94V-0 UL REGISTERED MATERIAL ID NUMBER" at 288.569,51.397 h1.52
  text "ADDITIONAL REQUIREMENTS:" at 287.87,47.094 h1.52
  text "MICROSECTION:" at 289.769,44.373 h1.52
  text "YES" at 312.775,44.373 h1.52
  text "REQUIRED" at 334.657,40.707 h1.52
  text "BARE BOARD ELEC. TEST:" at 289.769,40.634 h1.52
  text "NONE" at 322.935,40.634 h1.52
  text "X" at 331.66,40.634 h1.52
  text "PER ORDER" at 349.693,40.634 h1.52
  text "XX MIL VIAS REQUIRE NON-CONDUCTIVE FILL AND PLANARIZE" at 294.04,35.428 h1.5
  text "XX MIL VIAS REQUIRE CONDUCTIVE FILL AND PLANARIZE" at 294.243,32.787 h1.52
  text "OUTER XX MIL TRACES REQUIRE 50 OHM SINGLE-ENDED IMPEDANCE" at 294.218,28.637 h1.47
  text "LAYER 2 & 3 (INNER LAYERS) XX MIL WIDE, XX MIL SPACE / TRACES REQUIRE 100 OHM DIFFERENTIAL IMPEDANCE" at 294.015,22.65 h1.52
  text ".Layer_Name" at 14.656,-21.806 h1.52
M11 Gerber Information:
  lines w0.254: -7.417,-23.626 160.223,-23.626 ; -7.417,-18.462 160.274,-18.462 ; -7.417,-13.297 -7.417,-28.791 94.31,-28.791 160.274,-28.791 160.274,-13.297 -7.404,-13.297 -7.404,-28.791 32.614,-28.791 ; 55.194,-28.791 55.194,-13.297 ; 87.376,-18.462 87.376,-13.297 ; 108.712,-18.462 108.712,-13.297 ; 124.511,-28.956 124.511,-23.804
  text "ALL ARTWORK VIEWED FROM TOP SIDE" at -5.804,-16.654 h1.52
  text "BOARD #:" at 57.099,-16.654 h1.52
  text ".PRJ_Number" at 70.955,-16.654 h1.52
  text "REV:" at 92.405,-16.654 h1.52
  text ".PCB_Rev" at 99.809,-16.654 h1.52
  text "SVN REV:" at 113.69,-16.654 h1.52
  text ".VersionControl_RevNumber" at 126.543,-16.654 h1.52
  text "LAYER NAME =" at -5.804,-21.806 h1.52
  text "TID #:" at 57.099,-21.819 h1.52
  text ".TID" at 70.955,-21.819 h1.52
  text "PLOT NAME =" at -5.804,-27.034 h1.52
  text ".plot_File_Name" at 14.656,-27.034 h1.52
  text "GENERATED    :" at 57.15,-27.034 h1.52
  text ".Print_Date" at 79.235,-27.034 h1.52
  text ".Print_Time" at 97.752,-27.034 h1.52
  text "TEXAS INSTRUMENTS" at 129.87,-27.034 h1.52
M12 Stackup:
  drawing of 609 lines, arcs and shapes, not listed
  text "Layer" at 162.963,97.026 h1.52
  text "Name" at 173.375,97.026 h1.52
  text "Material" at 196.99,97.026 h1.52
  text "Thickness" at 218.828,97.026 h1.52
  text "Constant" at 235.334,97.026 h1.52
  text "Board Layer Stack" at 249.809,97.026 h1.52
  text "Top Overlay" at 173.375,93.978 h1.52
  text "Top Solder" at 173.375,90.93 h1.52
  text "Solder Resist" at 196.99,90.93 h1.52
  text "0.010mm" at 218.828,90.93 h1.52
  text "3.5" at 235.334,90.93 h1.52
  text "1" at 162.963,87.882 h1.52
  text "Top Layer" at 173.375,87.882 h1.52
  text "CF-004" at 196.99,87.882 h1.52
  text "0.070mm" at 218.828,87.882 h1.52
  text "Dielectric 7" at 173.375,84.834 h1.52
  text "PP-006" at 196.99,84.834 h1.52
  text "0.200mm" at 218.828,84.834 h1.52
  text "4.1" at 235.334,84.834 h1.52
  text "2" at 162.963,81.786 h1.52
  text "Layer 2" at 173.375,81.786 h1.52
  text "CF-004" at 196.99,81.786 h1.52
  text "0.105mm" at 218.828,81.786 h1.52
  text "Dielectric 1" at 173.375,78.738 h1.52
  text "PP-006" at 196.99,78.738 h1.52
  text "0.250mm" at 218.828,78.738 h1.52
  text "4.1" at 235.334,78.738 h1.52
  text "3" at 162.963,75.69 h1.52
  text "Layer 3" at 173.375,75.69 h1.52
  text "CF-004" at 196.99,75.69 h1.52
  text "0.105mm" at 218.828,75.69 h1.52
  text "Dielectric 2" at 173.375,72.642 h1.52
  text "PP-006" at 196.99,72.642 h1.52
  text "0.200mm" at 218.828,72.642 h1.52
  text "4.1" at 235.334,72.642 h1.52
  text "4" at 162.963,69.594 h1.52
  text "Layer 4" at 173.375,69.594 h1.52
  text "CF-004" at 196.99,69.594 h1.52
  text "0.105mm" at 218.828,69.594 h1.52
  text "Dielectric 3" at 173.375,66.546 h1.52
  text "PP-006" at 196.99,66.546 h1.52
  text "0.250mm" at 218.828,66.546 h1.52
  text "4.1" at 235.334,66.546 h1.52
  text "5" at 162.963,63.498 h1.52
  text "Layer 5" at 173.375,63.498 h1.52
  text "CF-004" at 196.99,63.498 h1.52
  text "0.105mm" at 218.828,63.498 h1.52
  text "Dielectric1" at 173.375,60.45 h1.52
  text "FR-4 High Tg" at 196.99,60.45 h1.52
  text "0.200mm" at 218.828,60.45 h1.52
  text "4.8" at 235.334,60.45 h1.52
  text "6" at 162.963,57.402 h1.52
  text "Layer 6" at 173.375,57.402 h1.52
  text "CF-004" at 196.99,57.402 h1.52
  text "0.105mm" at 218.828,57.402 h1.52
  text "Dielectric 4" at 173.375,54.354 h1.52
  text "PP-006" at 196.99,54.354 h1.52
  text "0.250mm" at 218.828,54.354 h1.52
  text "4.1" at 235.334,54.354 h1.52
  text "7" at 162.963,51.306 h1.52
  text "Layer 7" at 173.375,51.306 h1.52
  text "CF-004" at 196.99,51.306 h1.52
  text "0.105mm" at 218.828,51.306 h1.52
  text "Dielectric 5" at 173.375,48.258 h1.52
  text "PP-006" at 196.99,48.258 h1.52
  text "0.200mm" at 218.828,48.258 h1.52
  text "4.1" at 235.334,48.258 h1.52
  text "8" at 162.963,45.21 h1.52
  text "Layer 8" at 173.375,45.21 h1.52
  text "CF-004" at 196.99,45.21 h1.52
  text "0.105mm" at 218.828,45.21 h1.52
  text "Dielectric 6" at 173.375,42.162 h1.52
  text "PP-006" at 196.99,42.162 h1.52
  text "0.250mm" at 218.828,42.162 h1.52
  text "4.1" at 235.334,42.162 h1.52
  text "9" at 162.963,39.114 h1.52
  text "Layer 9" at 173.375,39.114 h1.52
  text "CF-004" at 196.99,39.114 h1.52
  text "0.105mm" at 218.828,39.114 h1.52
  text "Dielectric 8" at 173.375,36.066 h1.52
  text "PP-006" at 196.99,36.066 h1.52
  text "0.200mm" at 218.828,36.066 h1.52
  text "4.1" at 235.334,36.066 h1.52
  text "10" at 162.963,33.018 h1.52
  text "Bottom Layer 1" at 173.375,33.018 h1.52
  text "CF-004" at 196.99,33.018 h1.52
  text "0.070mm" at 218.828,33.018 h1.52
  text "Bottom Solder" at 173.375,29.97 h1.52
  text "Solder Resist" at 196.99,29.97 h1.52
  text "0.010mm" at 218.828,29.97 h1.52
  text "3.5" at 235.334,29.97 h1.52
  text "Bottom Overlay" at 173.375,26.922 h1.52
  text ".Layer_Name" at 14.656,-21.806 h1.52
M13 Component Bodies Top:
  text ".Layer_Name" at 14.656,-21.806 h1.52
M14 Component Bodies Bottom:
  text ".Layer_Name" at 14.656,-21.806 h1.52
M15 Courtyards Top:
  lines w0.254: 27.389,185 27.389,185.5 ; 27.389,186.162 27.389,186.75 ; 27.389,187.582 27.389,188 ; 36.889,185 36.889,185.5 ; 36.889,186.162 36.889,186.75 ; 36.889,187.582 36.889,188 ; 63.15,174.923 41,174.923 41,179.023 45.275,179.023 45.275,186.25 58.875,186.25 58.875,179.023 63.15,179.023 63.15,175 ; 27.389,185.5 27.389,179.023 26.639,179.023 26.639,176.023 37.639,176.023 37.639,179.023 36.889,179.023 36.889,185.5 ; 27.389,185.5 36.889,185.5 ; 27.389,188 27.389,194.897 26.639,194.897 26.639,197.897 37.639,197.897 37.639,194.897 36.889,194.897 36.889,188 ; 27.389,188 36.889,188 ; 41,195.023 41,199.123 63.15,199.123 63.15,195.023 58.875,195.023 58.875,187.25 45.275,187.25 45.275,195.023 41,195.023
  text "1.0mm" at 50.764,186.505 h0.5
  text "2.9mm" at 29.982,186.315 h0.76
  text ".Layer_Name" at 14.656,-21.806 h1.52
M16 Courtyards Bottom:
  text ".Layer_Name" at 14.656,-21.806 h1.52
Drill Drawing:
  circle w0.254: c172.399,116.544 r0.702
  lines w0.254: 171.697,113.035 172.048,113.035 172.399,112.684 172.75,113.035 173.101,113.035 172.75,113.386 173.101,113.737 172.75,113.737 172.399,114.088 172.048,113.737 171.697,113.737 172.048,113.386 171.697,113.035 ; 171.697,119 173.101,119 173.101,120.403 171.697,120.403 171.697,119 ; 171.697,122.508 172.048,122.508 172.048,122.157 172.75,122.157 172.75,122.508 173.101,122.508 173.101,123.21 172.75,123.21 172.75,123.561 172.048,123.561 172.048,123.21 171.697,123.21 171.697,122.508
  lines w0.305: 170.425,111.737 253.403,111.737 ; 170.425,124.368 253.403,124.368 ; 179.007,108.579 179.007,127.525 ; 187.44,108.579 187.44,127.525 ; 203.608,108.579 203.608,127.525 ; 210.191,108.579 210.191,127.525 ; 219.72,108.579 219.72,127.525 ; 239.016,108.579 239.016,127.525 ; 170.425,108.579 253.403,108.579 253.403,127.525 170.425,127.525 170.425,108.579
  text "Symbol" at 172.32,125.315 h1.83
  text "Quantity" at 179.954,125.315 h1.83
  text "Finished Hole Size" at 188.387,125.315 h1.83
  text "Plated" at 204.556,125.315 h1.83
  text "Hole Type" at 211.138,125.315 h1.83
  text "Drill Layer Pair" at 220.667,125.315 h1.83
  text "Hole Tolerance" at 239.963,125.315 h1.83
  text "944" at 179.954,122.157 h1.52
  text "11.81mil (0.300mm)" at 188.387,122.157 h1.52
  text "PTH" at 204.556,122.157 h1.52
  text "Round" at 211.138,122.157 h1.52
  text "(Mixed)" at 220.667,122.157 h1.52
  text "18" at 179.954,119 h1.52
  text "15.75mil (0.400mm)" at 188.387,119 h1.52
  text "PTH" at 204.556,119 h1.52
  text "Round" at 211.138,119 h1.52
  text "Top Layer - Bottom Layer 1" at 220.667,119 h1.52
  text "12" at 179.954,115.842 h1.52
  text "30.00mil (0.762mm)" at 188.387,115.842 h1.52
  text "PTH" at 204.556,115.842 h1.52
  text "Round" at 211.138,115.842 h1.52
  text "Top Layer - Bottom Layer 1" at 220.667,115.842 h1.52
  text "16" at 179.954,112.684 h1.52
  text "59.06mil (1.500mm)" at 188.387,112.684 h1.52
  text "PTH" at 204.556,112.684 h1.52
  text "Round" at 211.138,112.684 h1.52
  text "Top Layer - Bottom Layer 1" at 220.667,112.684 h1.52
  text "990 Total" at 179.954,109.526 h1.52
  text ".Layer_Name" at 14.656,-21.806 h1.52
M17 Embedded Cavity:
  text ".Layer_Name" at 14.656,-21.806 h1.52
M18 Embedded Assembly:
  text ".Layer_Name" at 14.656,-21.806 h1.52
M19 Embedded Keepout:
  lines w2: 19.284,4.103 22.532,4.103
  lines w3.2: 25.051,7.983 25.051,70.365 ; 26.449,76.453 39.384,76.453 ; 26.449,110.311 39.176,110.311 ; 26.449,146.453 39.256,146.453 39.256,140.9 ; 39.212,104.887 39.212,113.902 ; 39.371,5.936 39.371,68.275 ; 43.621,128.471 38.5,128.471 38.5,124.761 38.534,124.727 38.534,117.531 39.286,116.779 39.286,113.631 43.703,113.631 43.703,128.185
  text ".Layer_Name" at 14.656,-21.806 h1.52

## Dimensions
5,35 to 5.381,67 on M2 Board Dimensions
0,-10.16 to 25.4,-10.16 on M2 Board Dimensions
5,0 to 5,35 on M2 Board Dimensions
5,0 to 75,0 on M2 Board Dimensions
